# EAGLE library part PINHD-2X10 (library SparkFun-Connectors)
PIN HEADER

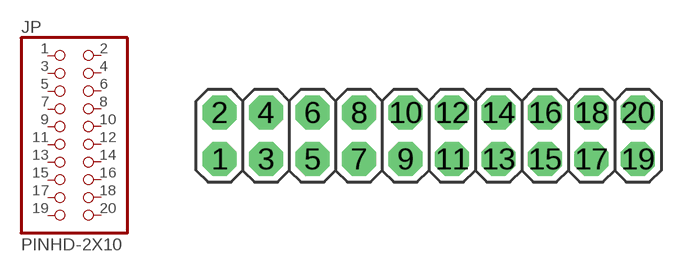
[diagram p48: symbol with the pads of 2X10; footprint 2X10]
Designator prefix JP

## PINHD-2X10  [2X10]
1  1  pas
2  2  pas
3  3  pas
4  4  pas
5  5  pas
6  6  pas
7  7  pas
8  8  pas
9  9  pas
10  10  pas
11  11  pas
12  12  pas
13  13  pas
14  14  pas
15  15  pas
16  16  pas
17  17  pas
18  18  pas
19  19  pas
20  20  pas

## Footprint 2X10 (pad centres in mm)
PIN HEADER
drill 1.016 pad 1.88 octagon: 1 -11.43,-1.27; 2 -11.43,1.27; 3 -8.89,-1.27; 4 -8.89,1.27; 5 -6.35,-1.27; 6 -6.35,1.27; 7 -3.81,-1.27; 8 -3.81,1.27; 9 -1.27,-1.27; 10 -1.27,1.27; 11 1.27,-1.27; 12 1.27,1.27; 13 3.81,-1.27; 14 3.81,1.27; 15 6.35,-1.27; 16 6.35,1.27; 17 8.89,-1.27; 18 8.89,1.27; 19 11.43,-1.27; 20 11.43,1.27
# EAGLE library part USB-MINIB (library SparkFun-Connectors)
Mini-USB "B" connector with 5th pin broken out. Created new symbol breaking out 5th "ID" pin in mini/micro USB connector spec. See: http://en.wikipedia.org/wiki/Mini_usb#Cables. Uses same footprint as 4-pin symbol. Also added pins to connect to mounting / shield pads if required (probably not generally needed as signals aren't shielded once they leave the connector).

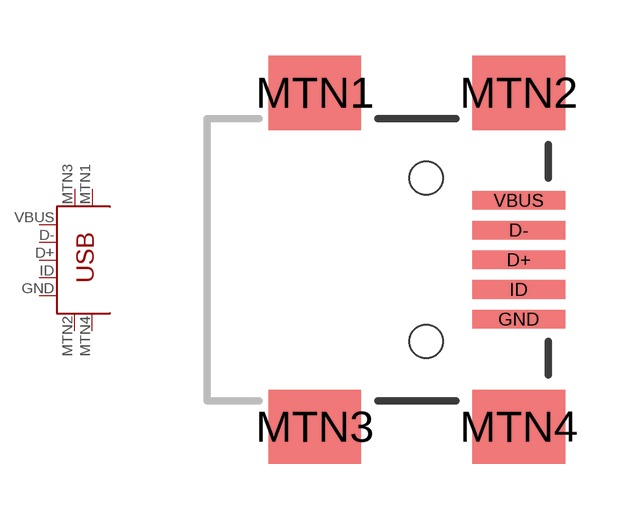
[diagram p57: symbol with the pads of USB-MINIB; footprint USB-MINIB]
Designator prefix -

## USB-MINIB-5PIN (PROD_ID: CONN-08193)  [USB-MINIB]
D+  D+
D-  D-
GND  GND
ID  ID
MTN1  MTN2
MTN2  MTN3
MTN3  MTN1
MTN4  MTN4
VBUS  VBUS

## Footprint USB-MINIB (pad centres in mm)
USB Series Mini-B Surface Mounted
smd 2.5 x 0.5: D+ 2.5,0; D- 2.5,0.8; GND 2.5,-1.6; ID 2.5,-0.8; VBUS 2.5,1.6
smd 2.5 x 2: MTN1 -3,4.5; MTN2 2.5,4.5; MTN3 -3,-4.5; MTN4 2.5,-4.5
hole 0.9 at 0,2.2
hole 0.9 at 0,-2.2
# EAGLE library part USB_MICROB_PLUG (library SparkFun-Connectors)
USB Micro-B connectors Some male, some female. Watch your step!

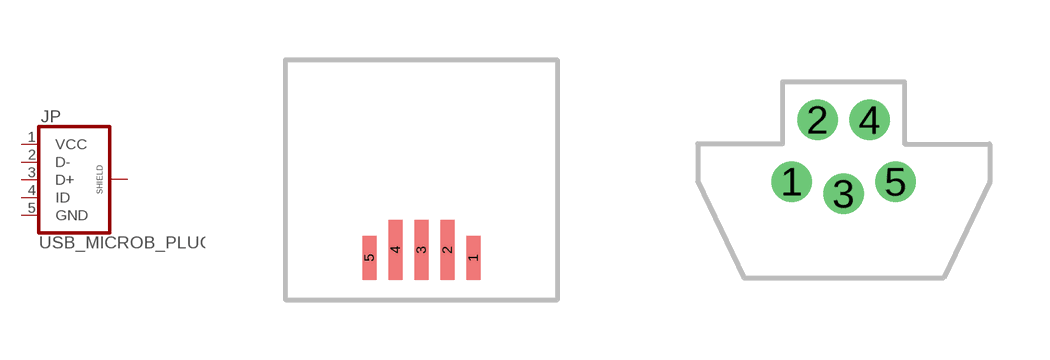
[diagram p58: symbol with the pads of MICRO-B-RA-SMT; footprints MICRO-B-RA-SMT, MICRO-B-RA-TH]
Designator prefix JP

## USB_MICROB_PLUG"  [MICRO-B-RA-SMT]
1  VCC
2  D-
3  D+
4  ID
5  GND

## USB_MICROB_PLUG-PTH  [MICRO-B-RA-TH]
Pads as for MICRO-B-RA-SMT

## USB_MICROB_PLUG-PTH2  [MICRO-B-TH]
Pads as for MICRO-B-RA-SMT

## USB_MICROB_PLUG-SMT (PROD_ID: CONN-09900)  [MICRO-B-SMT]
1  VCC
2  D-
3  D+
4  ID
5  GND
P$6  SHIELD

## USB_MICROB_PLUGCONN-11752 (PROD_ID: CONN-11752)  [USB-B-MICRO-SMD_V03]
D+1  D+
D-1  D-
GND1  GND
ID1  ID
SHIELD1  SHIELD
SHIELD2  SHIELD
SHIELD3  SHIELD
VBUS1  VCC

## Footprint MICRO-B-RA-SMT (pad centres in mm)
Package for an SMT Micro-B connector. Digikey part #H11613-ND *** Unproven***
smd 0.35 x 1.1: 1 1.3,-1.95; 5 -1.3,-1.95
smd 0.35 x 1.5: 2 0.65,-1.75; 3 0,-1.75; 4 -0.65,-1.75

## Footprint MICRO-B-RA-TH (pad centres in mm)
Micro B Right Angle through-hole PCB plug connector **Unproven** See digikey part #H11673TR-ND
drill 0.508 pad 0.9: 1 -1.3,-0.95; 2 -0.65,0.6; 3 0,-1.25; 4 0.65,0.6; 5 1.3,-0.95

## Footprint MICRO-B-TH (pad centres in mm)
Micro B USB Plug Assembly - Straight Through-hole **UNPROVEN** See Digikey part #H11497-ND
drill 0.6 pad 1: 1 -1.3,-0.775; 2 -0.65,0.775; 3 0,-0.775; 4 0.65,0.775; 5 1.3,-0.775
drill 1.2: P$1 -4.1,0; P$2 4.1,0

## Footprint MICRO-B-SMT (pad centres in mm)
USB Micro-B Plug Connector Manufacturer part #: ZX80-B-5SA Manufacturer: Hirose ***Unproven*** (Passed 1:1 printout test though!)
smd 0.4 x 2.2: 1 -1.3,0; 2 -0.65,0; 3 0,0; 4 0.65,0; 5 1.3,0
drill 1.016 pad 2.2: P$6 -3.121,3.183; P$7 -3.098,-0.027; P$8 3.122,3.16; P$9 3.108,-0.026
hole 3.3 at -8.275,2.17
hole 3.3 at 8.275,2.17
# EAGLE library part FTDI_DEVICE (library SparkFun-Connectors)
Connector which mates to FTDI basic or FTDI cable.

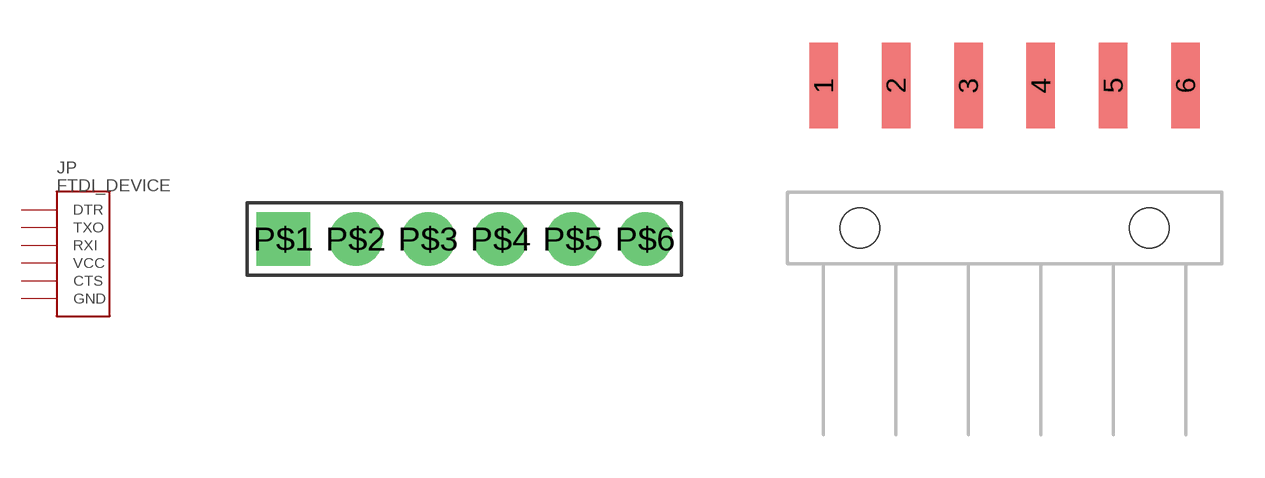
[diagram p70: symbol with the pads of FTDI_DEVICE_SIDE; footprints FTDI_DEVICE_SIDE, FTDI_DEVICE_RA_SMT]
Designator prefix JP

## FTDI_DEVICE  [FTDI_DEVICE_SIDE]
P$1  DTR
P$2  TXO
P$3  RXI
P$4  VCC
P$5  CTS
P$6  GND

## FTDI_DEVICERA_SMT (PROD_ID: CONN-08971)  [FTDI_DEVICE_RA_SMT]
1  DTR
2  TXO
3  RXI
4  VCC
5  CTS
6  GND

## Footprint FTDI_DEVICE_SIDE (pad centres in mm)
Package for devices meant to mate to an FTDI connector.
drill 1.016 pad 1.88 square: P$1 -6.35,0
drill 1.016 pad 1.88: P$2 -3.81,0; P$3 -1.27,0; P$4 1.27,0; P$5 3.81,0; P$6 6.35,0

## Footprint FTDI_DEVICE_RA_SMT (pad centres in mm)
Package for devices meant to mate to an FTDI connector.
smd 1 x 3: 1 -6.35,5; 2 -3.81,5; 3 -1.27,5; 4 1.27,5; 5 3.81,5; 6 6.35,5
hole 1.4 at -5.08,0
hole 1.4 at 5.08,0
